VERSION 5.7 ;
  NOWIREEXTENSIONATPIN ON ;
  DIVIDERCHAR "/" ;
  BUSBITCHARS "[]" ;
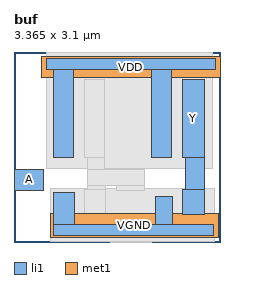
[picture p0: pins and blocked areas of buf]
MACRO buf
  CLASS BLOCK ;
  FOREIGN buf ;
  ORIGIN 1.060 0.385 ;
  SIZE 3.365 BY 3.100 ;
  PIN A
    ANTENNAGATEAREA 0.253500 ;
    PORT
      LAYER li1 ;
        RECT -1.045 0.460 -0.580 0.800 ;
    END
  END A
  PIN VDD
    ANTENNADIFFAREA 0.762000 ;
    PORT
      LAYER li1 ;
        RECT -0.535 2.430 2.235 2.605 ;
        RECT -0.415 0.990 -0.085 2.430 ;
        RECT 1.185 0.990 1.515 2.430 ;
      LAYER met1 ;
        RECT -0.610 2.300 2.305 2.635 ;
    END
  END VDD
  PIN VGND
    USE GROUND ;
    PORT
      LAYER li1 ;
        RECT -0.410 -0.105 -0.080 0.420 ;
        RECT 1.245 -0.105 1.520 0.360 ;
        RECT -0.410 -0.285 2.200 -0.105 ;
      LAYER met1 ;
        RECT -0.460 -0.305 2.270 0.085 ;
    END
  END VGND
  PIN Y
    ANTENNADIFFAREA 0.507000 ;
    PORT
      LAYER li1 ;
        RECT 1.690 0.990 2.040 2.260 ;
        RECT 1.740 0.470 2.040 0.990 ;
        RECT 1.690 0.065 2.040 0.470 ;
    END
  END Y
  OBS
      LAYER nwell ;
        RECT -0.530 0.810 2.180 2.715 ;
      LAYER pwell ;
        RECT -0.470 -0.380 2.205 0.485 ;
        RECT 0.515 -0.385 1.185 -0.380 ;
      LAYER li1 ;
        RECT 0.090 0.990 0.415 2.260 ;
        RECT 0.140 0.800 0.415 0.990 ;
        RECT 0.140 0.530 1.075 0.800 ;
        RECT 0.140 0.470 0.440 0.530 ;
        RECT 0.090 0.065 0.440 0.470 ;
        RECT 0.610 0.460 1.075 0.530 ;
  END
END buf
END LIBRARY

